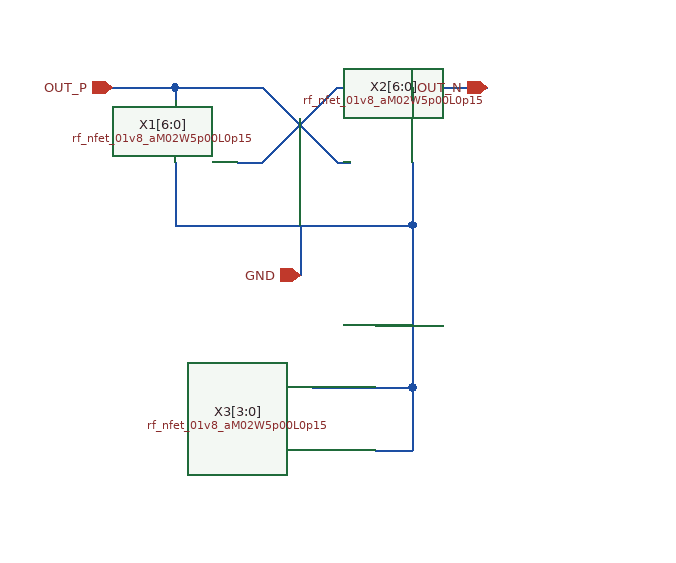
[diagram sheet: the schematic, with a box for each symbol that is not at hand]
v {xschem version=3.0.0 file_version=1.2 }
G {}
K {}
V {}
S {}
E {}
N 2650 -1590 2690 -1590 { lab=OUT_P}
N 2810 -1590 2850 -1590 { lab=OUT_N}
N 2780 -1590 2810 -1590 { lab=OUT_N}
N 2690 -1590 2720 -1590 { lab=OUT_P}
N 2720 -1530 2780 -1590 { lab=OUT_N}
N 2720 -1590 2780 -1530 { lab=OUT_P}
N 2600 -1590 2650 -1590 { lab=OUT_P}
N 2850 -1590 2900 -1590 { lab=OUT_N}
N 2750 -1480 2750 -1440 { lab=GND}
N 2810 -1350 2840 -1350 { lab=GND}
N 2810 -1400 2840 -1400 { lab=GND}
N 2810 -1300 2840 -1300 { lab=GND}
N 2840 -1350 2840 -1300 { lab=GND}
N 2700 -1530 2720 -1530 {
lab=OUT_N}
N 2780 -1530 2790 -1530 {
lab=OUT_P}
N 2650 -1590 2650 -1580 {
lab=OUT_P}
N 2840 -1590 2840 -1580 {
lab=OUT_N}
N 2650 -1480 2840 -1480 {
lab=GND}
N 2840 -1530 2840 -1480 {
lab=GND}
N 2650 -1530 2650 -1480 {
lab=GND}
N 2760 -1350 2840 -1350 {
lab=GND}
N 2840 -1480 2840 -1350 {
lab=GND}
C {rf_nfet_01v8_aM02W5p00L0p15.sym} 2720 -1460 0 1 {name=X1[6:0]}
C {rf_nfet_01v8_aM02W5p00L0p15.sym} 2770 -1460 0 0 {name=X2[6:0]}
C {devices/iopin.sym} 2750 -1440 1 0 {name=p1 lab=GND}
C {devices/iopin.sym} 2600 -1590 2 0 {name=p2 lab=OUT_P}
C {devices/iopin.sym} 2900 -1590 0 0 {name=p3 lab=OUT_N}
C {rf_nfet_01v8_aM02W5p00L0p15.sym} 2740 -1280 0 0 {name=X3[3:0]}
